VERSION 5.8 ;
BUSBITCHARS "[]" ;
DIVIDERCHAR "/" ;
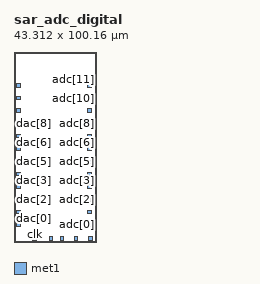
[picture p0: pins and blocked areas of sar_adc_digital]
MACRO sar_adc_digital
  CLASS BLOCK ;
  ORIGIN 0 0 ;
  FOREIGN sar_adc_digital 0 0 ;
  SIZE 43.312 BY 100.160 ;
  SYMMETRY X Y R90 ;
  PIN comp_p
    DIRECTION INOUT ;
    USE SIGNAL ;
    PORT
      LAYER met1 ;
      RECT 1.500 50.580 3.500 52.580 ;
    END
  END comp_p
  PIN dac[0]
    DIRECTION INOUT ;
    USE SIGNAL ;
    PORT
      LAYER met1 ;
      RECT 1.500 8.100 3.500 10.100 ;
    END
  END dac[0]
  PIN dac[1]
    DIRECTION INOUT ;
    USE SIGNAL ;
    PORT
      LAYER met1 ;
      RECT 1.500 14.780 3.500 16.780 ;
    END
  END dac[1]
  PIN dac[2]
    DIRECTION INOUT ;
    USE SIGNAL ;
    PORT
      LAYER met1 ;
      RECT 1.500 21.460 3.500 23.460 ;
    END
  END dac[2]
  PIN dac[3]
    DIRECTION INOUT ;
    USE SIGNAL ;
    PORT
      LAYER met1 ;
      RECT 1.500 28.140 3.500 30.140 ;
    END
  END dac[3]
  PIN dac[4]
    DIRECTION INOUT ;
    USE SIGNAL ;
    PORT
      LAYER met1 ;
      RECT 1.500 34.820 3.500 36.820 ;
    END
  END dac[4]
  PIN dac[5]
    DIRECTION INOUT ;
    USE SIGNAL ;
    PORT
      LAYER met1 ;
      RECT 1.500 41.500 3.500 43.500 ;
    END
  END dac[5]
  PIN dac[6]
    DIRECTION INOUT ;
    USE SIGNAL ;
    PORT
      LAYER met1 ;
      RECT 1.500 48.180 3.500 50.180 ;
    END
  END dac[6]
  PIN dac[7]
    DIRECTION INOUT ;
    USE SIGNAL ;
    PORT
      LAYER met1 ;
      RECT 1.500 54.860 3.500 56.860 ;
    END
  END dac[7]
  PIN dac[8]
    DIRECTION INOUT ;
    USE SIGNAL ;
    PORT
      LAYER met1 ;
      RECT 1.500 61.540 3.500 63.540 ;
    END
  END dac[8]
  PIN dac[9]
    DIRECTION INOUT ;
    USE SIGNAL ;
    PORT
      LAYER met1 ;
      RECT 1.500 68.220 3.500 70.220 ;
    END
  END dac[9]
  PIN dac[10]
    DIRECTION INOUT ;
    USE SIGNAL ;
    PORT
      LAYER met1 ;
      RECT 1.500 74.900 3.500 76.900 ;
    END
  END dac[10]
  PIN dac[11]
    DIRECTION INOUT ;
    USE SIGNAL ;
    PORT
      LAYER met1 ;
      RECT 1.500 81.580 3.500 83.580 ;
    END
  END dac[11]
  PIN sample_en
    DIRECTION INOUT ;
    USE SIGNAL ;
    PORT
      LAYER met1 ;
      RECT 38.650 60.596 40.650 62.596 ;
    END
  END sample_en
  PIN adc[0]
    DIRECTION INOUT ;
    USE SIGNAL ;
    PORT
      LAYER met1 ;
      RECT 38.650 8.100 40.650 10.100 ;
    END
  END adc[0]
  PIN adc[1]
    DIRECTION INOUT ;
    USE SIGNAL ;
    PORT
      LAYER met1 ;
      RECT 38.650 14.780 40.650 16.780 ;
    END
  END adc[1]
  PIN adc[2]
    DIRECTION INOUT ;
    USE SIGNAL ;
    PORT
      LAYER met1 ;
      RECT 38.650 21.460 40.650 23.460 ;
    END
  END adc[2]
  PIN adc[3]
    DIRECTION INOUT ;
    USE SIGNAL ;
    PORT
      LAYER met1 ;
      RECT 38.650 28.140 40.650 30.140 ;
    END
  END adc[3]
  PIN adc[4]
    DIRECTION INOUT ;
    USE SIGNAL ;
    PORT
      LAYER met1 ;
      RECT 38.650 34.820 40.650 36.820 ;
    END
  END adc[4]
  PIN adc[5]
    DIRECTION INOUT ;
    USE SIGNAL ;
    PORT
      LAYER met1 ;
      RECT 38.650 41.500 40.650 43.500 ;
    END
  END adc[5]
  PIN adc[6]
    DIRECTION INOUT ;
    USE SIGNAL ;
    PORT
      LAYER met1 ;
      RECT 38.650 48.180 40.650 50.180 ;
    END
  END adc[6]
  PIN adc[7]
    DIRECTION INOUT ;
    USE SIGNAL ;
    PORT
      LAYER met1 ;
      RECT 38.650 54.860 40.650 56.860 ;
    END
  END adc[7]
  PIN adc[8]
    DIRECTION INOUT ;
    USE SIGNAL ;
    PORT
      LAYER met1 ;
      RECT 38.650 61.540 40.650 63.540 ;
    END
  END adc[8]
  PIN adc[9]
    DIRECTION INOUT ;
    USE SIGNAL ;
    PORT
      LAYER met1 ;
      RECT 38.650 68.220 40.650 70.220 ;
    END
  END adc[9]
  PIN adc[10]
    DIRECTION INOUT ;
    USE SIGNAL ;
    PORT
      LAYER met1 ;
      RECT 38.650 74.900 40.650 76.900 ;
    END
  END adc[10]
  PIN adc[11]
    DIRECTION INOUT ;
    USE SIGNAL ;
    PORT
      LAYER met1 ;
      RECT 38.650 81.580 40.650 83.580 ;
    END
  END adc[11]
  PIN clk
    DIRECTION INOUT ;
    USE SIGNAL ;
    PORT
      LAYER met1 ;
      RECT 9.980 1.000 11.980 3.000 ;
    END
  END clk
  PIN rst_n
    DIRECTION INOUT ;
    USE SIGNAL ;
    PORT
      LAYER met1 ;
      RECT 18.460 1.000 20.460 3.000 ;
    END
  END rst_n
  PIN eoc
    DIRECTION INOUT ;
    USE SIGNAL ;
    PORT
      LAYER met1 ;
      RECT 24.320 1.000 26.320 3.000 ;
    END
  END eoc
  PIN sample_tick
    DIRECTION INOUT ;
    USE SIGNAL ;
    PORT
      LAYER met1 ;
      RECT 31.680 1.000 33.680 3.000 ;
    END
  END sample_tick
  PIN sar_clk_en
    DIRECTION INOUT ;
    USE SIGNAL ;
    PORT
      LAYER met1 ;
      RECT 39.312 1.000 41.312 3.000 ;
    END
  END sar_clk_en
END sar_adc_digital
END LIBRARY
